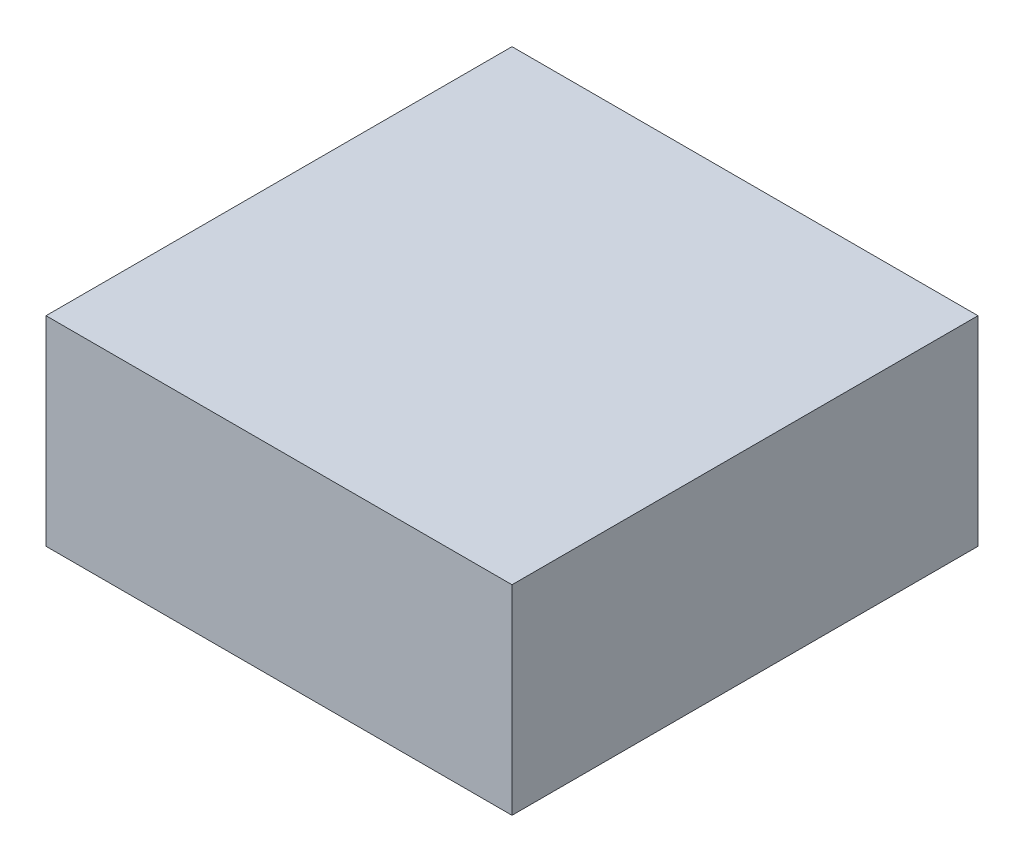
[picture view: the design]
ISO-10303-21;
HEADER;
FILE_DESCRIPTION(('STEP AP214'),'2;1');
FILE_NAME('part.step','',(''),(''),'','','');
FILE_SCHEMA(('AUTOMOTIVE_DESIGN { 1 0 10303 214 1 1 1 1 }'));
ENDSEC;
DATA;
#1=APPLICATION_CONTEXT('core data for automotive mechanical design processes');
#2=APPLICATION_PROTOCOL_DEFINITION('international standard','automotive_design',2000,#1);
#3=PRODUCT_CONTEXT('',#1,'mechanical');
#4=PRODUCT('Part','Part','',(#3));
#5=PRODUCT_RELATED_PRODUCT_CATEGORY('part','',(#4));
#6=PRODUCT_DEFINITION_FORMATION('','',#4);
#7=PRODUCT_DEFINITION_CONTEXT('part definition',#1,'design');
#8=PRODUCT_DEFINITION('design','',#6,#7);
#9=PRODUCT_DEFINITION_SHAPE('','',#8);
#10=(LENGTH_UNIT() NAMED_UNIT(*) SI_UNIT(.MILLI.,.METRE.));
#11=(NAMED_UNIT(*) PLANE_ANGLE_UNIT() SI_UNIT($,.RADIAN.));
#12=(NAMED_UNIT(*) SI_UNIT($,.STERADIAN.) SOLID_ANGLE_UNIT());
#13=UNCERTAINTY_MEASURE_WITH_UNIT(LENGTH_MEASURE(1.E-05),#10,'distance_accuracy_value','');
#14=(GEOMETRIC_REPRESENTATION_CONTEXT(3) GLOBAL_UNCERTAINTY_ASSIGNED_CONTEXT((#13)) GLOBAL_UNIT_ASSIGNED_CONTEXT((#10,
#11,#12)) REPRESENTATION_CONTEXT('',''));
#15=CARTESIAN_POINT('',(0.,0.,0.));
#16=DIRECTION('',(0.,0.,1.));
#17=DIRECTION('',(1.,0.,0.));
#18=AXIS2_PLACEMENT_3D('',#15,#16,#17);
#19=CARTESIAN_POINT('',(17.5,15.,17.5));
#20=DIRECTION('',(-1.,0.,0.));
#21=DIRECTION('',(0.,0.,1.));
#22=AXIS2_PLACEMENT_3D('',#19,#20,#21);
#23=PLANE('',#22);
#24=DIRECTION('',(0.,0.,-1.));
#25=VECTOR('',#24,1.);
#26=CARTESIAN_POINT('',(17.5,0.,17.5));
#27=LINE('',#26,#25);
#28=CARTESIAN_POINT('',(17.5,0.,17.5));
#29=VERTEX_POINT('',#28);
#30=CARTESIAN_POINT('',(17.5,0.,-17.5));
#31=VERTEX_POINT('',#30);
#32=EDGE_CURVE('E110',#29,#31,#27,.T.);
#33=ORIENTED_EDGE('',*,*,#32,.T.);
#34=DIRECTION('',(0.,-1.,0.));
#35=VECTOR('',#34,1.);
#36=CARTESIAN_POINT('',(17.5,15.,-17.5));
#37=LINE('',#36,#35);
#38=CARTESIAN_POINT('',(17.5,15.,-17.5));
#39=VERTEX_POINT('',#38);
#40=EDGE_CURVE('E12',#39,#31,#37,.T.);
#41=ORIENTED_EDGE('',*,*,#40,.F.);
#42=DIRECTION('',(0.,0.,-1.));
#43=VECTOR('',#42,1.);
#44=CARTESIAN_POINT('',(17.5,15.,17.5));
#45=LINE('',#44,#43);
#46=CARTESIAN_POINT('',(17.5,15.,17.5));
#47=VERTEX_POINT('',#46);
#48=EDGE_CURVE('E98',#47,#39,#45,.T.);
#49=ORIENTED_EDGE('',*,*,#48,.F.);
#50=DIRECTION('',(0.,-1.,0.));
#51=VECTOR('',#50,1.);
#52=CARTESIAN_POINT('',(17.5,15.,17.5));
#53=LINE('',#52,#51);
#54=EDGE_CURVE('E106',#47,#29,#53,.T.);
#55=ORIENTED_EDGE('',*,*,#54,.T.);
#56=EDGE_LOOP('',(#33,#41,#49,#55));
#57=FACE_BOUND('',#56,.T.);
#58=ADVANCED_FACE('F47',(#57),#23,.F.);
#59=CARTESIAN_POINT('',(-17.5,15.,-17.5));
#60=DIRECTION('',(0.,0.,1.));
#61=DIRECTION('',(1.,0.,0.));
#62=AXIS2_PLACEMENT_3D('',#59,#60,#61);
#63=PLANE('',#62);
#64=DIRECTION('',(-1.,0.,0.));
#65=VECTOR('',#64,1.);
#66=CARTESIAN_POINT('',(-17.5,0.,-17.5));
#67=LINE('',#66,#65);
#68=CARTESIAN_POINT('',(-17.5,0.,-17.5));
#69=VERTEX_POINT('',#68);
#70=EDGE_CURVE('E102',#31,#69,#67,.T.);
#71=ORIENTED_EDGE('',*,*,#70,.T.);
#72=DIRECTION('',(0.,-1.,0.));
#73=VECTOR('',#72,1.);
#74=CARTESIAN_POINT('',(-17.5,15.,-17.5));
#75=LINE('',#74,#73);
#76=CARTESIAN_POINT('',(-17.5,15.,-17.5));
#77=VERTEX_POINT('',#76);
#78=EDGE_CURVE('E55',#77,#69,#75,.T.);
#79=ORIENTED_EDGE('',*,*,#78,.F.);
#80=DIRECTION('',(-1.,0.,0.));
#81=VECTOR('',#80,1.);
#82=CARTESIAN_POINT('',(-17.5,15.,-17.5));
#83=LINE('',#82,#81);
#84=EDGE_CURVE('E93',#39,#77,#83,.T.);
#85=ORIENTED_EDGE('',*,*,#84,.F.);
#86=ORIENTED_EDGE('',*,*,#40,.T.);
#87=EDGE_LOOP('',(#71,#79,#85,#86));
#88=FACE_BOUND('',#87,.T.);
#89=ADVANCED_FACE('F101',(#88),#63,.F.);
#90=CARTESIAN_POINT('',(-17.5,15.,17.5));
#91=DIRECTION('',(1.,0.,0.));
#92=DIRECTION('',(0.,0.,-1.));
#93=AXIS2_PLACEMENT_3D('',#90,#91,#92);
#94=PLANE('',#93);
#95=DIRECTION('',(0.,0.,1.));
#96=VECTOR('',#95,1.);
#97=CARTESIAN_POINT('',(-17.5,0.,17.5));
#98=LINE('',#97,#96);
#99=CARTESIAN_POINT('',(-17.5,0.,17.5));
#100=VERTEX_POINT('',#99);
#101=EDGE_CURVE('E80',#69,#100,#98,.T.);
#102=ORIENTED_EDGE('',*,*,#101,.T.);
#103=DIRECTION('',(0.,-1.,0.));
#104=VECTOR('',#103,1.);
#105=CARTESIAN_POINT('',(-17.5,15.,17.5));
#106=LINE('',#105,#104);
#107=CARTESIAN_POINT('',(-17.5,15.,17.5));
#108=VERTEX_POINT('',#107);
#109=EDGE_CURVE('E103',#108,#100,#106,.T.);
#110=ORIENTED_EDGE('',*,*,#109,.F.);
#111=DIRECTION('',(0.,0.,1.));
#112=VECTOR('',#111,1.);
#113=CARTESIAN_POINT('',(-17.5,15.,17.5));
#114=LINE('',#113,#112);
#115=EDGE_CURVE('E96',#77,#108,#114,.T.);
#116=ORIENTED_EDGE('',*,*,#115,.F.);
#117=ORIENTED_EDGE('',*,*,#78,.T.);
#118=EDGE_LOOP('',(#102,#110,#116,#117));
#119=FACE_BOUND('',#118,.T.);
#120=ADVANCED_FACE('F104',(#119),#94,.F.);
#121=CARTESIAN_POINT('',(-17.5,15.,17.5));
#122=DIRECTION('',(0.,0.,-1.));
#123=DIRECTION('',(-1.,0.,0.));
#124=AXIS2_PLACEMENT_3D('',#121,#122,#123);
#125=PLANE('',#124);
#126=DIRECTION('',(1.,0.,0.));
#127=VECTOR('',#126,1.);
#128=CARTESIAN_POINT('',(-17.5,0.,17.5));
#129=LINE('',#128,#127);
#130=EDGE_CURVE('E86',#100,#29,#129,.T.);
#131=ORIENTED_EDGE('',*,*,#130,.T.);
#132=ORIENTED_EDGE('',*,*,#54,.F.);
#133=DIRECTION('',(1.,0.,0.));
#134=VECTOR('',#133,1.);
#135=CARTESIAN_POINT('',(-17.5,15.,17.5));
#136=LINE('',#135,#134);
#137=EDGE_CURVE('E63',#108,#47,#136,.T.);
#138=ORIENTED_EDGE('',*,*,#137,.F.);
#139=ORIENTED_EDGE('',*,*,#109,.T.);
#140=EDGE_LOOP('',(#131,#132,#138,#139));
#141=FACE_BOUND('',#140,.T.);
#142=ADVANCED_FACE('F117',(#141),#125,.F.);
#143=CARTESIAN_POINT('',(0.,15.,0.));
#144=DIRECTION('',(0.,-1.,0.));
#145=DIRECTION('',(0.,0.,-1.));
#146=AXIS2_PLACEMENT_3D('',#143,#144,#145);
#147=PLANE('',#146);
#148=ORIENTED_EDGE('',*,*,#48,.T.);
#149=ORIENTED_EDGE('',*,*,#84,.T.);
#150=ORIENTED_EDGE('',*,*,#115,.T.);
#151=ORIENTED_EDGE('',*,*,#137,.T.);
#152=EDGE_LOOP('',(#148,#149,#150,#151));
#153=FACE_BOUND('',#152,.T.);
#154=ADVANCED_FACE('F94',(#153),#147,.F.);
#155=CARTESIAN_POINT('',(0.,0.,0.));
#156=DIRECTION('',(0.,-1.,0.));
#157=DIRECTION('',(0.,0.,-1.));
#158=AXIS2_PLACEMENT_3D('',#155,#156,#157);
#159=PLANE('',#158);
#160=ORIENTED_EDGE('',*,*,#32,.F.);
#161=ORIENTED_EDGE('',*,*,#130,.F.);
#162=ORIENTED_EDGE('',*,*,#101,.F.);
#163=ORIENTED_EDGE('',*,*,#70,.F.);
#164=EDGE_LOOP('',(#160,#161,#162,#163));
#165=FACE_BOUND('',#164,.T.);
#166=ADVANCED_FACE('F120',(#165),#159,.T.);
#167=CLOSED_SHELL('',(#58,#89,#120,#142,#154,#166));
#168=MANIFOLD_SOLID_BREP('B2',#167);
#169=CARTESIAN_POINT('',(0.,4.,0.));
#170=DIRECTION('',(0.,-1.,0.));
#171=DIRECTION('',(0.,0.,-1.));
#172=AXIS2_PLACEMENT_3D('',#169,#170,#171);
#173=PLANE('',#172);
#174=CARTESIAN_POINT('',(0.,4.,0.));
#175=DIRECTION('',(0.,-1.,0.));
#176=DIRECTION('',(0.,0.,-1.));
#177=AXIS2_PLACEMENT_3D('',#174,#175,#176);
#178=CIRCLE('',#177,7.5);
#179=CARTESIAN_POINT('',(0.,4.,-7.5));
#180=VERTEX_POINT('',#179);
#181=EDGE_CURVE('E456',#180,#180,#178,.T.);
#182=ORIENTED_EDGE('',*,*,#181,.T.);
#183=EDGE_LOOP('',(#182));
#184=FACE_BOUND('',#183,.T.);
#185=ADVANCED_FACE('F170',(#184),#173,.T.);
#186=CARTESIAN_POINT('',(0.,4.,0.));
#187=DIRECTION('',(0.,-1.,0.));
#188=DIRECTION('',(0.,0.,-1.));
#189=AXIS2_PLACEMENT_3D('',#186,#187,#188);
#190=CONICAL_SURFACE('',#189,7.5,0.643501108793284);
#191=CARTESIAN_POINT('',(0.,0.,0.));
#192=DIRECTION('',(0.,-1.,0.));
#193=DIRECTION('',(0.,0.,-1.));
#194=AXIS2_PLACEMENT_3D('',#191,#192,#193);
#195=CIRCLE('',#194,10.5);
#196=CARTESIAN_POINT('',(0.,0.,-10.5));
#197=VERTEX_POINT('',#196);
#198=EDGE_CURVE('E453',#197,#197,#195,.T.);
#199=ORIENTED_EDGE('',*,*,#198,.T.);
#200=EDGE_LOOP('',(#199));
#201=FACE_BOUND('',#200,.T.);
#202=ORIENTED_EDGE('',*,*,#181,.F.);
#203=EDGE_LOOP('',(#202));
#204=FACE_BOUND('',#203,.T.);
#205=ADVANCED_FACE('F563',(#201,#204),#190,.F.);
#206=CARTESIAN_POINT('',(0.,0.,-10.5));
#207=DIRECTION('',(0.,-1.,0.));
#208=DIRECTION('',(0.,0.,-1.));
#209=AXIS2_PLACEMENT_3D('',#206,#207,#208);
#210=PLANE('',#209);
#211=ORIENTED_EDGE('',*,*,#198,.F.);
#212=EDGE_LOOP('',(#211));
#213=FACE_BOUND('',#212,.T.);
#214=CARTESIAN_POINT('',(0.,0.,0.));
#215=DIRECTION('',(0.,-1.,0.));
#216=DIRECTION('',(0.,0.,-1.));
#217=AXIS2_PLACEMENT_3D('',#214,#215,#216);
#218=CIRCLE('',#217,14.875);
#219=CARTESIAN_POINT('',(0.,0.,-14.875));
#220=VERTEX_POINT('',#219);
#221=EDGE_CURVE('E363',#220,#220,#218,.T.);
#222=ORIENTED_EDGE('',*,*,#221,.T.);
#223=EDGE_LOOP('',(#222));
#224=FACE_BOUND('',#223,.T.);
#225=ADVANCED_FACE('F571',(#213,#224),#210,.T.);
#226=CARTESIAN_POINT('',(0.,0.,0.));
#227=DIRECTION('',(0.,-1.,0.));
#228=DIRECTION('',(0.,0.,-1.));
#229=AXIS2_PLACEMENT_3D('',#226,#227,#228);
#230=CONICAL_SURFACE('',#229,14.875,0.643501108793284);
#231=CARTESIAN_POINT('',(0.,5.9,0.));
#232=DIRECTION('',(0.,-1.,0.));
#233=DIRECTION('',(0.,0.,-1.));
#234=AXIS2_PLACEMENT_3D('',#231,#232,#233);
#235=CIRCLE('',#234,10.45);
#236=CARTESIAN_POINT('',(0.,5.9,-10.45));
#237=VERTEX_POINT('',#236);
#238=EDGE_CURVE('E366',#237,#237,#235,.T.);
#239=ORIENTED_EDGE('',*,*,#238,.T.);
#240=EDGE_LOOP('',(#239));
#241=FACE_BOUND('',#240,.T.);
#242=ORIENTED_EDGE('',*,*,#221,.F.);
#243=EDGE_LOOP('',(#242));
#244=FACE_BOUND('',#243,.T.);
#245=ADVANCED_FACE('F641',(#241,#244),#230,.T.);
#246=CARTESIAN_POINT('',(0.,4.7,0.));
#247=DIRECTION('',(0.,-1.,0.));
#248=DIRECTION('',(0.,0.,-1.));
#249=AXIS2_PLACEMENT_3D('',#246,#247,#248);
#250=TOROIDAL_SURFACE('',#249,8.85,2.);
#251=CARTESIAN_POINT('',(0.,6.7,0.));
#252=DIRECTION('',(0.,-1.,0.));
#253=DIRECTION('',(0.,0.,-1.));
#254=AXIS2_PLACEMENT_3D('',#251,#252,#253);
#255=CIRCLE('',#254,8.85);
#256=CARTESIAN_POINT('',(0.,6.7,-8.85));
#257=VERTEX_POINT('',#256);
#258=EDGE_CURVE('E935',#257,#257,#255,.T.);
#259=ORIENTED_EDGE('',*,*,#258,.T.);
#260=EDGE_LOOP('',(#259));
#261=FACE_BOUND('',#260,.T.);
#262=ORIENTED_EDGE('',*,*,#238,.F.);
#263=EDGE_LOOP('',(#262));
#264=FACE_BOUND('',#263,.T.);
#265=ADVANCED_FACE('F627',(#261,#264),#250,.T.);
#266=CARTESIAN_POINT('',(0.,6.7,-8.85));
#267=DIRECTION('',(0.,1.,0.));
#268=DIRECTION('',(0.,0.,1.));
#269=AXIS2_PLACEMENT_3D('',#266,#267,#268);
#270=PLANE('',#269);
#271=DIRECTION('',(0.390432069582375,0.,-0.92063173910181));
#272=VECTOR('',#271,1.);
#273=CARTESIAN_POINT('',(-4.19533930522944,6.7,0.0590000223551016));
#274=LINE('',#273,#272);
#275=CARTESIAN_POINT('',(-4.44324414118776,6.7,0.643555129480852));
#276=VERTEX_POINT('',#275);
#277=CARTESIAN_POINT('',(-5.27922504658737,6.7,2.61478294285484));
#278=VERTEX_POINT('',#277);
#279=EDGE_CURVE('E415',#276,#278,#274,.F.);
#280=ORIENTED_EDGE('',*,*,#279,.F.);
#281=CARTESIAN_POINT('',(-3.97468030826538,6.7,0.901510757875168));
#282=DIRECTION('',(0.,1.,0.));
#283=DIRECTION('',(-0.435109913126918,0.,-0.900377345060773));
#284=AXIS2_PLACEMENT_3D('',#281,#282,#283);
#285=ELLIPSE('',#284,0.555470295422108,0.5);
#286=CARTESIAN_POINT('',(-3.88564907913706,6.7,0.374095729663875));
#287=VERTEX_POINT('',#286);
#288=EDGE_CURVE('E192',#276,#287,#285,.F.);
#289=ORIENTED_EDGE('',*,*,#288,.T.);
#290=DIRECTION('',(0.96393747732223,0.,0.266128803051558));
#291=VECTOR('',#290,1.);
#292=CARTESIAN_POINT('',(-1.45344472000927,6.7,1.04559118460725));
#293=LINE('',#292,#291);
#294=CARTESIAN_POINT('',(-2.14143502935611,6.7,0.85564729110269));
#295=VERTEX_POINT('',#294);
#296=EDGE_CURVE('E185',#295,#287,#293,.F.);
#297=ORIENTED_EDGE('',*,*,#296,.F.);
#298=CARTESIAN_POINT('',(-2.34213496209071,6.7,1.35223225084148));
#299=DIRECTION('',(0.,1.,0.));
#300=DIRECTION('',(0.866025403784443,0.,-0.499999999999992));
#301=AXIS2_PLACEMENT_3D('',#298,#299,#300);
#302=ELLIPSE('',#301,0.561470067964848,0.5);
#303=CARTESIAN_POINT('',(-1.81172980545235,6.7,1.42671349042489));
#304=VERTEX_POINT('',#303);
#305=EDGE_CURVE('E411',#295,#304,#302,.F.);
#306=ORIENTED_EDGE('',*,*,#305,.T.);
#307=DIRECTION('',(-0.251494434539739,0.,0.967858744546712));
#308=VECTOR('',#307,1.);
#309=CARTESIAN_POINT('',(-2.42648733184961,6.7,3.79256484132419));
#310=LINE('',#309,#308);
#311=CARTESIAN_POINT('',(-2.26680094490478,6.7,3.17802294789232));
#312=VERTEX_POINT('',#311);
#313=EDGE_CURVE('E403',#312,#304,#310,.F.);
#314=ORIENTED_EDGE('',*,*,#313,.F.);
#315=CARTESIAN_POINT('',(-2.7680713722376,6.7,2.99141873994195));
#316=DIRECTION('',(0.,1.,0.));
#317=DIRECTION('',(0.562194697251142,0.,0.827004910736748));
#318=AXIS2_PLACEMENT_3D('',#315,#316,#317);
#319=ELLIPSE('',#318,0.555470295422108,0.5);
#320=CARTESIAN_POINT('',(-2.77895716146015,6.7,3.52618473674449));
#321=VERTEX_POINT('',#320);
#322=EDGE_CURVE('E400',#312,#321,#319,.F.);
#323=ORIENTED_EDGE('',*,*,#322,.T.);
#324=DIRECTION('',(-0.9925065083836,0.,-0.122191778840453));
#325=VECTOR('',#324,1.);
#326=CARTESIAN_POINT('',(-5.85784082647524,6.7,3.14713002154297));
#327=LINE('',#326,#325);
#328=CARTESIAN_POINT('',(-4.90408097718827,6.7,3.26455153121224));
#329=VERTEX_POINT('',#328);
#330=EDGE_CURVE('E405',#329,#321,#327,.F.);
#331=ORIENTED_EDGE('',*,*,#330,.F.);
#332=CARTESIAN_POINT('',(-4.75713974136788,6.7,2.74653591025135));
#333=DIRECTION('',(0.,1.,0.));
#334=DIRECTION('',(-0.866025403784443,0.,0.499999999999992));
#335=AXIS2_PLACEMENT_3D('',#332,#333,#334);
#336=ELLIPSE('',#335,0.584262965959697,0.5);
#337=EDGE_CURVE('E408',#329,#278,#336,.F.);
#338=ORIENTED_EDGE('',*,*,#337,.T.);
#339=EDGE_LOOP('',(#280,#289,#297,#306,#314,#323,#331,#338));
#340=FACE_BOUND('',#339,.T.);
#341=DIRECTION('',(-0.992506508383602,0.,0.122191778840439));
#342=VECTOR('',#341,1.);
#343=CARTESIAN_POINT('',(2.14876517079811,6.7,3.60377040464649));
#344=LINE('',#343,#342);
#345=CARTESIAN_POINT('',(2.7789571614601,6.7,3.52618473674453));
#346=VERTEX_POINT('',#345);
#347=CARTESIAN_POINT('',(4.90408097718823,6.7,3.2645515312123));
#348=VERTEX_POINT('',#347);
#349=EDGE_CURVE('E395',#346,#348,#344,.F.);
#350=ORIENTED_EDGE('',*,*,#349,.F.);
#351=CARTESIAN_POINT('',(2.76807137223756,6.7,2.99141873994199));
#352=DIRECTION('',(0.,1.,0.));
#353=DIRECTION('',(-0.562194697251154,0.,0.827004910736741));
#354=AXIS2_PLACEMENT_3D('',#351,#352,#353);
#355=ELLIPSE('',#354,0.555470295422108,0.5);
#356=CARTESIAN_POINT('',(2.26680094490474,6.7,3.17802294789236));
#357=VERTEX_POINT('',#356);
#358=EDGE_CURVE('E397',#346,#357,#355,.F.);
#359=ORIENTED_EDGE('',*,*,#358,.T.);
#360=DIRECTION('',(-0.251494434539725,0.,-0.967858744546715));
#361=VECTOR('',#360,1.);
#362=CARTESIAN_POINT('',(1.63223088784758,6.7,0.735924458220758));
#363=LINE('',#362,#361);
#364=CARTESIAN_POINT('',(1.81172980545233,6.7,1.42671349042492));
#365=VERTEX_POINT('',#364);
#366=EDGE_CURVE('E393',#365,#357,#363,.F.);
#367=ORIENTED_EDGE('',*,*,#366,.F.);
#368=CARTESIAN_POINT('',(2.3421349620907,6.7,1.35223225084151));
#369=DIRECTION('',(0.,1.,0.));
#370=DIRECTION('',(-0.866025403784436,0.,-0.500000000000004));
#371=AXIS2_PLACEMENT_3D('',#368,#369,#370);
#372=ELLIPSE('',#371,0.561470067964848,0.5);
#373=CARTESIAN_POINT('',(2.1414350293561,6.7,0.855647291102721));
#374=VERTEX_POINT('',#373);
#375=EDGE_CURVE('E390',#365,#374,#372,.F.);
#376=ORIENTED_EDGE('',*,*,#375,.T.);
#377=DIRECTION('',(0.963937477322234,0.,-0.266128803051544));
#378=VECTOR('',#377,1.);
#379=CARTESIAN_POINT('',(4.49770116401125,6.7,0.205117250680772));
#380=LINE('',#379,#378);
#381=CARTESIAN_POINT('',(3.88564907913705,6.7,0.37409572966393));
#382=VERTEX_POINT('',#381);
#383=EDGE_CURVE('E382',#382,#374,#380,.F.);
#384=ORIENTED_EDGE('',*,*,#383,.F.);
#385=CARTESIAN_POINT('',(3.97468030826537,6.7,0.901510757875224));
#386=DIRECTION('',(0.,1.,0.));
#387=DIRECTION('',(0.435109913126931,0.,-0.900377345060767));
#388=AXIS2_PLACEMENT_3D('',#385,#386,#387);
#389=ELLIPSE('',#388,0.555470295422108,0.5);
#390=CARTESIAN_POINT('',(4.44324414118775,6.7,0.643555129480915));
#391=VERTEX_POINT('',#390);
#392=EDGE_CURVE('E379',#382,#391,#389,.F.);
#393=ORIENTED_EDGE('',*,*,#392,.T.);
#394=DIRECTION('',(0.390432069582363,0.,0.920631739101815));
#395=VECTOR('',#394,1.);
#396=CARTESIAN_POINT('',(5.65441496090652,6.7,3.49947395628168));
#397=LINE('',#396,#395);
#398=CARTESIAN_POINT('',(5.27922504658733,6.7,2.61478294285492));
#399=VERTEX_POINT('',#398);
#400=EDGE_CURVE('E384',#399,#391,#397,.F.);
#401=ORIENTED_EDGE('',*,*,#400,.F.);
#402=CARTESIAN_POINT('',(4.75713974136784,6.7,2.74653591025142));
#403=DIRECTION('',(0.,1.,0.));
#404=DIRECTION('',(0.866025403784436,0.,0.500000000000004));
#405=AXIS2_PLACEMENT_3D('',#402,#403,#404);
#406=ELLIPSE('',#405,0.584262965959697,0.5);
#407=EDGE_CURVE('E387',#399,#348,#406,.F.);
#408=ORIENTED_EDGE('',*,*,#407,.T.);
#409=EDGE_LOOP('',(#350,#359,#367,#376,#384,#393,#401,#408));
#410=FACE_BOUND('',#409,.T.);
#411=DIRECTION('',(0.602074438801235,0.,0.79843996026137));
#412=VECTOR('',#411,1.);
#413=CARTESIAN_POINT('',(2.04657413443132,6.7,-3.66277042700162));
#414=LINE('',#413,#412);
#415=CARTESIAN_POINT('',(1.66428697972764,6.7,-4.16973986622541));
#416=VERTEX_POINT('',#415);
#417=CARTESIAN_POINT('',(0.375144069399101,6.7,-5.87933447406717));
#418=VERTEX_POINT('',#417);
#419=EDGE_CURVE('E374',#416,#418,#414,.F.);
#420=ORIENTED_EDGE('',*,*,#419,.F.);
#421=CARTESIAN_POINT('',(1.2066089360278,6.7,-3.89292949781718));
#422=DIRECTION('',(0.,1.,0.));
#423=DIRECTION('',(0.997304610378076,0.,0.0733724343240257));
#424=AXIS2_PLACEMENT_3D('',#421,#422,#423);
#425=ELLIPSE('',#424,0.555470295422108,0.5);
#426=CARTESIAN_POINT('',(1.6188481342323,6.7,-3.55211867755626));
#427=VERTEX_POINT('',#426);
#428=EDGE_CURVE('E376',#416,#427,#425,.F.);
#429=ORIENTED_EDGE('',*,*,#428,.T.);
#430=DIRECTION('',(-0.712443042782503,0.,0.701729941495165));
#431=VECTOR('',#430,1.);
#432=CARTESIAN_POINT('',(-0.178786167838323,6.7,-1.78151564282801));
#433=LINE('',#432,#431);
#434=CARTESIAN_POINT('',(0.329705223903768,6.7,-2.28236078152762));
#435=VERTEX_POINT('',#434);
#436=EDGE_CURVE('E372',#435,#427,#433,.F.);
#437=ORIENTED_EDGE('',*,*,#436,.F.);
#438=CARTESIAN_POINT('',(0.,6.7,-2.704464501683));
#439=DIRECTION('',(0.,1.,0.));
#440=DIRECTION('',(0.,0.,1.));
#441=AXIS2_PLACEMENT_3D('',#438,#439,#440);
#442=ELLIPSE('',#441,0.561470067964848,0.5);
#443=CARTESIAN_POINT('',(-0.329705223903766,6.7,-2.28236078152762));
#444=VERTEX_POINT('',#443);
#445=EDGE_CURVE('E360',#435,#444,#442,.F.);
#446=ORIENTED_EDGE('',*,*,#445,.T.);
#447=DIRECTION('',(-0.712443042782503,0.,-0.701729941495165));
#448=VECTOR('',#447,1.);
#449=CARTESIAN_POINT('',(-2.07121383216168,6.7,-3.99768209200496));
#450=LINE('',#449,#448);
#451=CARTESIAN_POINT('',(-1.6188481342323,6.7,-3.55211867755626));
#452=VERTEX_POINT('',#451);
#453=EDGE_CURVE('E352',#452,#444,#450,.F.);
#454=ORIENTED_EDGE('',*,*,#453,.F.);
#455=CARTESIAN_POINT('',(-1.20660893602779,6.7,-3.89292949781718));
#456=DIRECTION('',(0.,1.,0.));
#457=DIRECTION('',(-0.997304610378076,0.,0.0733724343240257));
#458=AXIS2_PLACEMENT_3D('',#455,#456,#457);
#459=ELLIPSE('',#458,0.555470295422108,0.5);
#460=CARTESIAN_POINT('',(-1.66428697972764,6.7,-4.16973986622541));
#461=VERTEX_POINT('',#460);
#462=EDGE_CURVE('E45',#452,#461,#459,.F.);
#463=ORIENTED_EDGE('',*,*,#462,.T.);
#464=DIRECTION('',(0.602074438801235,0.,-0.79843996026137));
#465=VECTOR('',#464,1.);
#466=CARTESIAN_POINT('',(0.20342586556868,6.7,-6.64660397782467));
#467=LINE('',#466,#465);
#468=CARTESIAN_POINT('',(-0.375144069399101,6.7,-5.87933447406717));
#469=VERTEX_POINT('',#468);
#470=EDGE_CURVE('E346',#469,#461,#467,.F.);
#471=ORIENTED_EDGE('',*,*,#470,.F.);
#472=CARTESIAN_POINT('',(0.,6.7,-5.49307182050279));
#473=DIRECTION('',(0.,1.,0.));
#474=DIRECTION('',(0.,0.,-1.));
#475=AXIS2_PLACEMENT_3D('',#472,#473,#474);
#476=ELLIPSE('',#475,0.584262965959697,0.5);
#477=EDGE_CURVE('E351',#469,#418,#476,.F.);
#478=ORIENTED_EDGE('',*,*,#477,.T.);
#479=EDGE_LOOP('',(#420,#429,#437,#446,#454,#463,#471,#478));
#480=FACE_BOUND('',#479,.T.);
#481=ORIENTED_EDGE('',*,*,#258,.F.);
#482=EDGE_LOOP('',(#481));
#483=FACE_BOUND('',#482,.T.);
#484=ADVANCED_FACE('F356',(#340,#410,#480,#483),#270,.T.);
#485=CARTESIAN_POINT('',(0.,7.,0.));
#486=DIRECTION('',(0.,-1.,0.));
#487=DIRECTION('',(0.,0.,-1.));
#488=AXIS2_PLACEMENT_3D('',#485,#486,#487);
#489=PLANE('',#488);
#490=DIRECTION('',(0.602074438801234,0.,-0.79843996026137));
#491=VECTOR('',#490,1.);
#492=CARTESIAN_POINT('',(-2.97828959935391,7.,-2.24581950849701));
#493=LINE('',#492,#491);
#494=CARTESIAN_POINT('',(-0.375144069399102,7.,-5.69797638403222));
#495=VERTEX_POINT('',#494);
#496=CARTESIAN_POINT('',(-1.51949906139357,7.,-4.18039201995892));
#497=VERTEX_POINT('',#496);
#498=EDGE_CURVE('E445',#495,#497,#493,.F.);
#499=ORIENTED_EDGE('',*,*,#498,.T.);
#500=CARTESIAN_POINT('',(-1.06182101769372,7.,-3.90358165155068));
#501=DIRECTION('',(0.,-1.,0.));
#502=DIRECTION('',(-0.997304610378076,0.,0.0733724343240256));
#503=AXIS2_PLACEMENT_3D('',#500,#501,#502);
#504=ELLIPSE('',#503,0.555470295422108,0.5);
#505=CARTESIAN_POINT('',(-1.47406021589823,7.,-3.56277083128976));
#506=VERTEX_POINT('',#505);
#507=EDGE_CURVE('E337',#497,#506,#504,.F.);
#508=ORIENTED_EDGE('',*,*,#507,.T.);
#509=DIRECTION('',(-0.712443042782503,0.,-0.701729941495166));
#510=VECTOR('',#509,1.);
#511=CARTESIAN_POINT('',(1.05531699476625,7.,-1.07142820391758));
#512=LINE('',#511,#510);
#513=CARTESIAN_POINT('',(-0.329705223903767,7.,-2.43562365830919));
#514=VERTEX_POINT('',#513);
#515=EDGE_CURVE('E447',#506,#514,#512,.F.);
#516=ORIENTED_EDGE('',*,*,#515,.T.);
#517=CARTESIAN_POINT('',(0.,7.,-2.85772737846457));
#518=DIRECTION('',(0.,-1.,0.));
#519=DIRECTION('',(0.,0.,1.));
#520=AXIS2_PLACEMENT_3D('',#517,#518,#519);
#521=ELLIPSE('',#520,0.561470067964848,0.5);
#522=CARTESIAN_POINT('',(0.329705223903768,7.,-2.43562365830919));
#523=VERTEX_POINT('',#522);
#524=EDGE_CURVE('E521',#514,#523,#521,.F.);
#525=ORIENTED_EDGE('',*,*,#524,.T.);
#526=DIRECTION('',(-0.712443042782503,0.,0.701729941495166));
#527=VECTOR('',#526,1.);
#528=CARTESIAN_POINT('',(-1.05531699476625,7.,-1.07142820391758));
#529=LINE('',#528,#527);
#530=CARTESIAN_POINT('',(1.47406021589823,7.,-3.56277083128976));
#531=VERTEX_POINT('',#530);
#532=EDGE_CURVE('E450',#523,#531,#529,.F.);
#533=ORIENTED_EDGE('',*,*,#532,.T.);
#534=CARTESIAN_POINT('',(1.06182101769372,7.,-3.90358165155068));
#535=DIRECTION('',(0.,-1.,0.));
#536=DIRECTION('',(0.997304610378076,0.,0.0733724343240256));
#537=AXIS2_PLACEMENT_3D('',#534,#535,#536);
#538=ELLIPSE('',#537,0.555470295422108,0.5);
#539=CARTESIAN_POINT('',(1.51949906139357,7.,-4.18039201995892));
#540=VERTEX_POINT('',#539);
#541=EDGE_CURVE('E341',#531,#540,#538,.F.);
#542=ORIENTED_EDGE('',*,*,#541,.T.);
#543=DIRECTION('',(0.602074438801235,0.,0.79843996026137));
#544=VECTOR('',#543,1.);
#545=CARTESIAN_POINT('',(2.97828959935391,7.,-2.24581950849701));
#546=LINE('',#545,#544);
#547=CARTESIAN_POINT('',(0.375144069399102,7.,-5.69797638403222));
#548=VERTEX_POINT('',#547);
#549=EDGE_CURVE('E442',#540,#548,#546,.F.);
#550=ORIENTED_EDGE('',*,*,#549,.T.);
#551=CARTESIAN_POINT('',(0.,7.,-5.31171373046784));
#552=DIRECTION('',(0.,-1.,0.));
#553=DIRECTION('',(0.,0.,-1.));
#554=AXIS2_PLACEMENT_3D('',#551,#552,#553);
#555=ELLIPSE('',#554,0.584262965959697,0.5);
#556=EDGE_CURVE('E519',#548,#495,#555,.F.);
#557=ORIENTED_EDGE('',*,*,#556,.T.);
#558=EDGE_LOOP('',(#499,#508,#516,#525,#533,#542,#550,#557));
#559=FACE_BOUND('',#558,.T.);
#560=ADVANCED_FACE('F539',(#559),#489,.F.);
#561=CARTESIAN_POINT('',(1.67832694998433,5.72260212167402,-3.85822485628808));
#562=DIRECTION('',(0.434430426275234,-0.900138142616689,0.0319613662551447));
#563=DIRECTION('',(0.900598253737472,0.434652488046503,0.));
#564=AXIS2_PLACEMENT_3D('',#561,#562,#563);
#565=CYLINDRICAL_SURFACE('',#564,0.5);
#566=ORIENTED_EDGE('',*,*,#428,.F.);
#567=DIRECTION('',(-0.434430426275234,0.900138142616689,-0.0319613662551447));
#568=VECTOR('',#567,1.);
#569=CARTESIAN_POINT('',(2.05347101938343,5.89361219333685,-4.14110730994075));
#570=LINE('',#569,#568);
#571=EDGE_CURVE('E529',#540,#416,#570,.F.);
#572=ORIENTED_EDGE('',*,*,#571,.F.);
#573=ORIENTED_EDGE('',*,*,#541,.F.);
#574=DIRECTION('',(-0.434430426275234,0.900138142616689,-0.0319613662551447));
#575=VECTOR('',#574,1.);
#576=CARTESIAN_POINT('',(1.61416158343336,6.70971051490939,-3.55246347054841));
#577=LINE('',#576,#575);
#578=EDGE_CURVE('E524',#427,#531,#577,.T.);
#579=ORIENTED_EDGE('',*,*,#578,.F.);
#580=EDGE_LOOP('',(#566,#572,#573,#579));
#581=FACE_BOUND('',#580,.T.);
#582=ADVANCED_FACE('F172',(#581),#565,.T.);
#583=CARTESIAN_POINT('',(0.,5.6974225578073,-2.19227149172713));
#584=DIRECTION('',(0.,-0.890519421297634,0.454945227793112));
#585=DIRECTION('',(0.,-0.454945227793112,-0.890519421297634));
#586=AXIS2_PLACEMENT_3D('',#583,#584,#585);
#587=CYLINDRICAL_SURFACE('',#586,0.5);
#588=ORIENTED_EDGE('',*,*,#445,.F.);
#589=DIRECTION('',(0.,0.890519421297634,-0.454945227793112));
#590=VECTOR('',#589,1.);
#591=CARTESIAN_POINT('',(0.329705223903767,5.86843262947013,-1.85753275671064));
#592=LINE('',#591,#590);
#593=EDGE_CURVE('E526',#523,#435,#592,.F.);
#594=ORIENTED_EDGE('',*,*,#593,.F.);
#595=ORIENTED_EDGE('',*,*,#524,.F.);
#596=DIRECTION('',(0.,0.890519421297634,-0.454945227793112));
#597=VECTOR('',#596,1.);
#598=CARTESIAN_POINT('',(-0.329705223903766,6.7662848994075,-2.31622416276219));
#599=LINE('',#598,#597);
#600=EDGE_CURVE('E513',#444,#514,#599,.T.);
#601=ORIENTED_EDGE('',*,*,#600,.F.);
#602=EDGE_LOOP('',(#588,#594,#595,#601));
#603=FACE_BOUND('',#602,.T.);
#604=ADVANCED_FACE('F551',(#603),#587,.T.);
#605=CARTESIAN_POINT('',(0.,6.,-1.6));
#606=DIRECTION('',(0.659410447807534,0.342020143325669,0.669477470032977));
#607=DIRECTION('',(0.712443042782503,0.,-0.701729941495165));
#608=AXIS2_PLACEMENT_3D('',#605,#606,#607);
#609=PLANE('',#608);
#610=ORIENTED_EDGE('',*,*,#593,.T.);
#611=ORIENTED_EDGE('',*,*,#436,.T.);
#612=ORIENTED_EDGE('',*,*,#578,.T.);
#613=ORIENTED_EDGE('',*,*,#532,.F.);
#614=EDGE_LOOP('',(#610,#611,#612,#613));
#615=FACE_BOUND('',#614,.T.);
#616=ADVANCED_FACE('F546',(#615),#609,.T.);
#617=CARTESIAN_POINT('',(-1.67832694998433,5.72260212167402,-3.85822485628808));
#618=DIRECTION('',(-0.434430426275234,-0.900138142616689,0.0319613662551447));
#619=DIRECTION('',(0.900598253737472,-0.434652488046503,0.));
#620=AXIS2_PLACEMENT_3D('',#617,#618,#619);
#621=CYLINDRICAL_SURFACE('',#620,0.5);
#622=ORIENTED_EDGE('',*,*,#462,.F.);
#623=DIRECTION('',(0.434430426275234,0.900138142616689,-0.0319613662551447));
#624=VECTOR('',#623,1.);
#625=CARTESIAN_POINT('',(-2.00803217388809,5.89361219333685,-3.52348612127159));
#626=LINE('',#625,#624);
#627=EDGE_CURVE('E515',#506,#452,#626,.F.);
#628=ORIENTED_EDGE('',*,*,#627,.F.);
#629=ORIENTED_EDGE('',*,*,#507,.F.);
#630=DIRECTION('',(0.434430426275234,0.900138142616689,-0.0319613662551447));
#631=VECTOR('',#630,1.);
#632=CARTESIAN_POINT('',(-1.58739848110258,6.85931266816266,-4.17539660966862));
#633=LINE('',#632,#631);
#634=EDGE_CURVE('E332',#461,#497,#633,.T.);
#635=ORIENTED_EDGE('',*,*,#634,.F.);
#636=EDGE_LOOP('',(#622,#628,#629,#635));
#637=FACE_BOUND('',#636,.T.);
#638=ADVANCED_FACE('F334',(#637),#621,.T.);
#639=CARTESIAN_POINT('',(-2.25,6.,-3.81616644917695));
#640=DIRECTION('',(-0.659410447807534,0.342020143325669,0.669477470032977));
#641=DIRECTION('',(0.712443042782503,0.,0.701729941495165));
#642=AXIS2_PLACEMENT_3D('',#639,#640,#641);
#643=PLANE('',#642);
#644=ORIENTED_EDGE('',*,*,#627,.T.);
#645=ORIENTED_EDGE('',*,*,#453,.T.);
#646=ORIENTED_EDGE('',*,*,#600,.T.);
#647=ORIENTED_EDGE('',*,*,#515,.F.);
#648=EDGE_LOOP('',(#644,#645,#646,#647));
#649=FACE_BOUND('',#648,.T.);
#650=ADVANCED_FACE('F552',(#649),#643,.T.);
#651=CARTESIAN_POINT('',(0.,5.60873322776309,-6.15277201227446));
#652=DIRECTION('',(0.,-0.855779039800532,-0.517341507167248));
#653=DIRECTION('',(0.,0.517341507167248,-0.855779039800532));
#654=AXIS2_PLACEMENT_3D('',#651,#652,#653);
#655=CYLINDRICAL_SURFACE('',#654,0.5);
#656=ORIENTED_EDGE('',*,*,#477,.F.);
#657=DIRECTION('',(0.,0.855779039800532,0.517341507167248));
#658=VECTOR('',#657,1.);
#659=CARTESIAN_POINT('',(-0.375144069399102,5.77974329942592,-6.43565446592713));
#660=LINE('',#659,#658);
#661=EDGE_CURVE('E342',#495,#469,#660,.F.);
#662=ORIENTED_EDGE('',*,*,#661,.F.);
#663=ORIENTED_EDGE('',*,*,#556,.F.);
#664=DIRECTION('',(0.,0.855779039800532,0.517341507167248));
#665=VECTOR('',#664,1.);
#666=CARTESIAN_POINT('',(0.375144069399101,7.10077598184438,-5.63705458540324));
#667=LINE('',#666,#665);
#668=EDGE_CURVE('E178',#418,#548,#667,.T.);
#669=ORIENTED_EDGE('',*,*,#668,.F.);
#670=EDGE_LOOP('',(#656,#662,#663,#669));
#671=FACE_BOUND('',#670,.T.);
#672=ADVANCED_FACE('F541',(#671),#655,.T.);
#673=CARTESIAN_POINT('',(0.,6.,-6.8));
#674=DIRECTION('',(-0.750288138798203,0.342020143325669,-0.565764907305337));
#675=DIRECTION('',(-0.602074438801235,0.,0.79843996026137));
#676=AXIS2_PLACEMENT_3D('',#673,#674,#675);
#677=PLANE('',#676);
#678=ORIENTED_EDGE('',*,*,#661,.T.);
#679=ORIENTED_EDGE('',*,*,#470,.T.);
#680=ORIENTED_EDGE('',*,*,#634,.T.);
#681=ORIENTED_EDGE('',*,*,#498,.F.);
#682=EDGE_LOOP('',(#678,#679,#680,#681));
#683=FACE_BOUND('',#682,.T.);
#684=ADVANCED_FACE('F347',(#683),#677,.T.);
#685=CARTESIAN_POINT('',(2.25,6.,-3.81616644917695));
#686=DIRECTION('',(0.750288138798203,0.342020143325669,-0.565764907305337));
#687=DIRECTION('',(-0.602074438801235,0.,-0.79843996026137));
#688=AXIS2_PLACEMENT_3D('',#685,#686,#687);
#689=PLANE('',#688);
#690=ORIENTED_EDGE('',*,*,#571,.T.);
#691=ORIENTED_EDGE('',*,*,#419,.T.);
#692=ORIENTED_EDGE('',*,*,#668,.T.);
#693=ORIENTED_EDGE('',*,*,#549,.F.);
#694=EDGE_LOOP('',(#690,#691,#692,#693));
#695=FACE_BOUND('',#694,.T.);
#696=ADVANCED_FACE('F534',(#695),#689,.T.);
#697=CARTESIAN_POINT('',(0.,7.,0.));
#698=DIRECTION('',(0.,-1.,0.));
#699=DIRECTION('',(0.866025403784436,0.,0.500000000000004));
#700=AXIS2_PLACEMENT_3D('',#697,#698,#699);
#701=PLANE('',#700);
#702=DIRECTION('',(0.390432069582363,0.,0.920631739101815));
#703=VECTOR('',#702,1.);
#704=CARTESIAN_POINT('',(3.43408154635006,7.,-1.45636469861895));
#705=LINE('',#704,#703);
#706=CARTESIAN_POINT('',(5.12216433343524,7.,2.52410389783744));
#707=VERTEX_POINT('',#706);
#708=CARTESIAN_POINT('',(4.38007521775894,7.,0.77427122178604));
#709=VERTEX_POINT('',#708);
#710=EDGE_CURVE('E433',#707,#709,#705,.F.);
#711=ORIENTED_EDGE('',*,*,#710,.T.);
#712=CARTESIAN_POINT('',(3.91151138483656,7.,1.03222685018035));
#713=DIRECTION('',(0.,-1.,0.));
#714=DIRECTION('',(0.435109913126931,0.,-0.900377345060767));
#715=AXIS2_PLACEMENT_3D('',#712,#713,#714);
#716=ELLIPSE('',#715,0.555470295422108,0.5);
#717=CARTESIAN_POINT('',(3.82248015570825,7.,0.504811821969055));
#718=VERTEX_POINT('',#717);
#719=EDGE_CURVE('E501',#709,#718,#716,.F.);
#720=ORIENTED_EDGE('',*,*,#719,.T.);
#721=DIRECTION('',(0.963937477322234,0.,-0.266128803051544));
#722=VECTOR('',#721,1.);
#723=CARTESIAN_POINT('',(0.400225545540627,7.,1.44964542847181));
#724=LINE('',#723,#722);
#725=CARTESIAN_POINT('',(2.27416457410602,7.,0.932278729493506));
#726=VERTEX_POINT('',#725);
#727=EDGE_CURVE('E436',#718,#726,#724,.F.);
#728=ORIENTED_EDGE('',*,*,#727,.T.);
#729=CARTESIAN_POINT('',(2.47486450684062,7.,1.4288636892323));
#730=DIRECTION('',(0.,-1.,0.));
#731=DIRECTION('',(-0.866025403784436,0.,-0.500000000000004));
#732=AXIS2_PLACEMENT_3D('',#729,#730,#731);
#733=ELLIPSE('',#732,0.561470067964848,0.5);
#734=CARTESIAN_POINT('',(1.94445935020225,7.,1.5033449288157));
#735=VERTEX_POINT('',#734);
#736=EDGE_CURVE('E499',#726,#735,#733,.F.);
#737=ORIENTED_EDGE('',*,*,#736,.T.);
#738=DIRECTION('',(-0.251494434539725,0.,-0.967858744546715));
#739=VECTOR('',#738,1.);
#740=CARTESIAN_POINT('',(1.45554254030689,7.,-0.378217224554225));
#741=LINE('',#740,#739);
#742=CARTESIAN_POINT('',(2.34841993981,7.,3.05795900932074));
#743=VERTEX_POINT('',#742);
#744=EDGE_CURVE('E439',#735,#743,#741,.F.);
#745=ORIENTED_EDGE('',*,*,#744,.T.);
#746=CARTESIAN_POINT('',(2.84969036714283,7.,2.87135480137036));
#747=DIRECTION('',(0.,-1.,0.));
#748=DIRECTION('',(-0.562194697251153,0.,0.82700491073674));
#749=AXIS2_PLACEMENT_3D('',#746,#747,#748);
#750=ELLIPSE('',#749,0.555470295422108,0.5);
#751=CARTESIAN_POINT('',(2.86057615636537,7.,3.40612079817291));
#752=VERTEX_POINT('',#751);
#753=EDGE_CURVE('E497',#743,#752,#750,.F.);
#754=ORIENTED_EDGE('',*,*,#753,.T.);
#755=DIRECTION('',(-0.992506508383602,0.,0.122191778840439));
#756=VECTOR('',#755,1.);
#757=CARTESIAN_POINT('',(0.455791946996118,7.,3.70218420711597));
#758=LINE('',#757,#756);
#759=CARTESIAN_POINT('',(4.74702026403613,7.,3.17387248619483));
#760=VERTEX_POINT('',#759);
#761=EDGE_CURVE('E430',#752,#760,#758,.F.);
#762=ORIENTED_EDGE('',*,*,#761,.T.);
#763=CARTESIAN_POINT('',(4.60007902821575,7.,2.65585686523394));
#764=DIRECTION('',(0.,-1.,0.));
#765=DIRECTION('',(0.866025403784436,0.,0.500000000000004));
#766=AXIS2_PLACEMENT_3D('',#763,#764,#765);
#767=ELLIPSE('',#766,0.584262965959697,0.5);
#768=EDGE_CURVE('E495',#760,#707,#767,.F.);
#769=ORIENTED_EDGE('',*,*,#768,.T.);
#770=EDGE_LOOP('',(#711,#720,#728,#737,#745,#754,#762,#769));
#771=FACE_BOUND('',#770,.T.);
#772=ADVANCED_FACE('F612',(#771),#701,.F.);
#773=CARTESIAN_POINT('',(2.50215726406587,5.72260212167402,3.38258620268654));
#774=DIRECTION('',(-0.244894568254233,-0.900138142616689,0.360247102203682));
#775=DIRECTION('',(0.,-0.371561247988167,-0.928408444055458));
#776=AXIS2_PLACEMENT_3D('',#773,#774,#775);
#777=CYLINDRICAL_SURFACE('',#776,0.5);
#778=ORIENTED_EDGE('',*,*,#358,.F.);
#779=DIRECTION('',(0.244894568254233,0.900138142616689,-0.360247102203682));
#780=VECTOR('',#779,1.);
#781=CARTESIAN_POINT('',(2.5595686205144,5.89361219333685,3.84891172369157));
#782=LINE('',#781,#780);
#783=EDGE_CURVE('E510',#752,#346,#782,.F.);
#784=ORIENTED_EDGE('',*,*,#783,.F.);
#785=ORIENTED_EDGE('',*,*,#753,.F.);
#786=DIRECTION('',(0.244894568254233,0.900138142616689,-0.360247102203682));
#787=VECTOR('',#786,1.);
#788=CARTESIAN_POINT('',(2.26944281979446,6.70971051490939,3.17413667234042));
#789=LINE('',#788,#787);
#790=EDGE_CURVE('E503',#357,#743,#789,.T.);
#791=ORIENTED_EDGE('',*,*,#790,.F.);
#792=EDGE_LOOP('',(#778,#784,#785,#791));
#793=FACE_BOUND('',#792,.T.);
#794=ADVANCED_FACE('F609',(#793),#777,.T.);
#795=CARTESIAN_POINT('',(1.8985628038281,5.6974225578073,1.09613574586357));
#796=DIRECTION('',(-0.393994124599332,-0.890519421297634,-0.227472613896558));
#797=DIRECTION('',(0.914493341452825,-0.40460094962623,0.));
#798=AXIS2_PLACEMENT_3D('',#795,#796,#797);
#799=CYLINDRICAL_SURFACE('',#798,0.5);
#800=ORIENTED_EDGE('',*,*,#375,.F.);
#801=DIRECTION('',(0.393994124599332,0.890519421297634,0.227472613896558));
#802=VECTOR('',#801,1.);
#803=CARTESIAN_POINT('',(1.44381794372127,5.86843262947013,1.21429947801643));
#804=LINE('',#803,#802);
#805=EDGE_CURVE('E505',#735,#365,#804,.F.);
#806=ORIENTED_EDGE('',*,*,#805,.F.);
#807=ORIENTED_EDGE('',*,*,#736,.F.);
#808=DIRECTION('',(0.393994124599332,0.890519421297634,0.227472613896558));
#809=VECTOR('',#808,1.);
#810=CARTESIAN_POINT('',(2.17076157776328,6.7662848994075,0.872578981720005));
#811=LINE('',#810,#809);
#812=EDGE_CURVE('E485',#374,#726,#811,.T.);
#813=ORIENTED_EDGE('',*,*,#812,.F.);
#814=EDGE_LOOP('',(#800,#806,#807,#813));
#815=FACE_BOUND('',#814,.T.);
#816=ADVANCED_FACE('F606',(#815),#799,.T.);
#817=CARTESIAN_POINT('',(1.3856406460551,6.,0.800000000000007));
#818=DIRECTION('',(-0.909489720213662,0.342020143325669,0.236327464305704));
#819=DIRECTION('',(-0.351990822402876,-0.93600345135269,0.));
#820=AXIS2_PLACEMENT_3D('',#817,#818,#819);
#821=PLANE('',#820);
#822=ORIENTED_EDGE('',*,*,#805,.T.);
#823=ORIENTED_EDGE('',*,*,#366,.T.);
#824=ORIENTED_EDGE('',*,*,#790,.T.);
#825=ORIENTED_EDGE('',*,*,#744,.F.);
#826=EDGE_LOOP('',(#822,#823,#824,#825));
#827=FACE_BOUND('',#826,.T.);
#828=ADVANCED_FACE('F599',(#827),#821,.T.);
#829=CARTESIAN_POINT('',(4.18048421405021,5.72260212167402,0.475638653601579));
#830=DIRECTION('',(0.189535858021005,-0.900138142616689,-0.392208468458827));
#831=DIRECTION('',(0.,0.399448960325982,-0.916755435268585));
#832=AXIS2_PLACEMENT_3D('',#829,#830,#831);
#833=CYLINDRICAL_SURFACE('',#832,0.5);
#834=ORIENTED_EDGE('',*,*,#392,.F.);
#835=DIRECTION('',(-0.189535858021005,0.900138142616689,0.392208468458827));
#836=VECTOR('',#835,1.);
#837=CARTESIAN_POINT('',(4.05544457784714,5.89361219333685,0.0227361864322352));
#838=LINE('',#837,#836);
#839=EDGE_CURVE('E487',#718,#382,#838,.F.);
#840=ORIENTED_EDGE('',*,*,#839,.F.);
#841=ORIENTED_EDGE('',*,*,#719,.F.);
#842=DIRECTION('',(-0.189535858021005,0.900138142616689,0.392208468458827));
#843=VECTOR('',#842,1.);
#844=CARTESIAN_POINT('',(4.40969877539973,6.85931266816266,0.712970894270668));
#845=LINE('',#844,#843);
#846=EDGE_CURVE('E493',#391,#709,#845,.T.);
#847=ORIENTED_EDGE('',*,*,#846,.F.);
#848=EDGE_LOOP('',(#834,#840,#841,#847));
#849=FACE_BOUND('',#848,.T.);
#850=ADVANCED_FACE('F595',(#849),#833,.T.);
#851=CARTESIAN_POINT('',(4.4298970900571,6.,-0.0404739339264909));
#852=DIRECTION('',(-0.250079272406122,0.342020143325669,-0.905804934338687));
#853=DIRECTION('',(0.,0.935531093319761,0.353244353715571));
#854=AXIS2_PLACEMENT_3D('',#851,#852,#853);
#855=PLANE('',#854);
#856=ORIENTED_EDGE('',*,*,#839,.T.);
#857=ORIENTED_EDGE('',*,*,#383,.T.);
#858=ORIENTED_EDGE('',*,*,#812,.T.);
#859=ORIENTED_EDGE('',*,*,#727,.F.);
#860=EDGE_LOOP('',(#856,#857,#858,#859));
#861=FACE_BOUND('',#860,.T.);
#862=ADVANCED_FACE('F598',(#861),#855,.T.);
#863=CARTESIAN_POINT('',(5.32845686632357,5.60873322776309,3.07638600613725));
#864=DIRECTION('',(0.448030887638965,-0.855779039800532,0.258670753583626));
#865=DIRECTION('',(0.88593122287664,0.463816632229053,0.));
#866=AXIS2_PLACEMENT_3D('',#863,#864,#865);
#867=CYLINDRICAL_SURFACE('',#866,0.5);
#868=ORIENTED_EDGE('',*,*,#407,.F.);
#869=DIRECTION('',(-0.448030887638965,0.855779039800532,-0.258670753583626));
#870=VECTOR('',#869,1.);
#871=CARTESIAN_POINT('',(5.76101229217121,5.77974329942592,2.8929429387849));
#872=LINE('',#871,#870);
#873=EDGE_CURVE('E490',#707,#399,#872,.F.);
#874=ORIENTED_EDGE('',*,*,#873,.F.);
#875=ORIENTED_EDGE('',*,*,#768,.F.);
#876=DIRECTION('',(-0.448030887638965,0.855779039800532,-0.258670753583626));
#877=VECTOR('',#876,1.);
#878=CARTESIAN_POINT('',(4.6942604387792,7.10077598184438,3.14341158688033));
#879=LINE('',#878,#877);
#880=EDGE_CURVE('E508',#348,#760,#879,.T.);
#881=ORIENTED_EDGE('',*,*,#880,.F.);
#882=EDGE_LOOP('',(#868,#874,#875,#881));
#883=FACE_BOUND('',#882,.T.);
#884=ADVANCED_FACE('F601',(#883),#867,.T.);
#885=CARTESIAN_POINT('',(5.88897274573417,6.,3.40000000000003));
#886=DIRECTION('',(0.865110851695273,0.342020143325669,-0.366886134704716));
#887=DIRECTION('',(-0.390432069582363,0.,-0.920631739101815));
#888=AXIS2_PLACEMENT_3D('',#885,#886,#887);
#889=PLANE('',#888);
#890=ORIENTED_EDGE('',*,*,#873,.T.);
#891=ORIENTED_EDGE('',*,*,#400,.T.);
#892=ORIENTED_EDGE('',*,*,#846,.T.);
#893=ORIENTED_EDGE('',*,*,#710,.F.);
#894=EDGE_LOOP('',(#890,#891,#892,#893));
#895=FACE_BOUND('',#894,.T.);
#896=ADVANCED_FACE('F604',(#895),#889,.T.);
#897=CARTESIAN_POINT('',(2.17989709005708,6.,3.85664038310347));
#898=DIRECTION('',(0.114822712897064,0.342020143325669,0.932651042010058));
#899=DIRECTION('',(0.,-0.938860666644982,0.344297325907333));
#900=AXIS2_PLACEMENT_3D('',#897,#898,#899);
#901=PLANE('',#900);
#902=ORIENTED_EDGE('',*,*,#783,.T.);
#903=ORIENTED_EDGE('',*,*,#349,.T.);
#904=ORIENTED_EDGE('',*,*,#880,.T.);
#905=ORIENTED_EDGE('',*,*,#761,.F.);
#906=EDGE_LOOP('',(#902,#903,#904,#905));
#907=FACE_BOUND('',#906,.T.);
#908=ADVANCED_FACE('F661',(#907),#901,.T.);
#909=CARTESIAN_POINT('',(0.,7.,0.));
#910=DIRECTION('',(0.,-1.,0.));
#911=DIRECTION('',(-0.866025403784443,0.,0.499999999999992));
#912=AXIS2_PLACEMENT_3D('',#909,#910,#911);
#913=PLANE('',#912);
#914=DIRECTION('',(-0.9925065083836,0.,-0.122191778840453));
#915=VECTOR('',#914,1.);
#916=CARTESIAN_POINT('',(-0.455791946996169,7.,3.70218420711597));
#917=LINE('',#916,#915);
#918=CARTESIAN_POINT('',(-4.74702026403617,7.,3.17387248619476));
#919=VERTEX_POINT('',#918);
#920=CARTESIAN_POINT('',(-2.86057615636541,7.,3.40612079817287));
#921=VERTEX_POINT('',#920);
#922=EDGE_CURVE('E421',#919,#921,#917,.F.);
#923=ORIENTED_EDGE('',*,*,#922,.T.);
#924=CARTESIAN_POINT('',(-2.84969036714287,7.,2.87135480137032));
#925=DIRECTION('',(0.,-1.,0.));
#926=DIRECTION('',(0.562194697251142,0.,0.827004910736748));
#927=AXIS2_PLACEMENT_3D('',#924,#925,#926);
#928=ELLIPSE('',#927,0.555470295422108,0.5);
#929=CARTESIAN_POINT('',(-2.34841993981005,7.,3.0579590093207));
#930=VERTEX_POINT('',#929);
#931=EDGE_CURVE('E475',#921,#930,#928,.F.);
#932=ORIENTED_EDGE('',*,*,#931,.T.);
#933=DIRECTION('',(-0.251494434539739,0.,0.967858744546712));
#934=VECTOR('',#933,1.);
#935=CARTESIAN_POINT('',(-1.45554254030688,7.,-0.378217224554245));
#936=LINE('',#935,#934);
#937=CARTESIAN_POINT('',(-1.94445935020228,7.,1.50334492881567));
#938=VERTEX_POINT('',#937);
#939=EDGE_CURVE('E424',#930,#938,#936,.F.);
#940=ORIENTED_EDGE('',*,*,#939,.T.);
#941=CARTESIAN_POINT('',(-2.47486450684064,7.,1.42886368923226));
#942=DIRECTION('',(0.,-1.,0.));
#943=DIRECTION('',(0.866025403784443,0.,-0.499999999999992));
#944=AXIS2_PLACEMENT_3D('',#941,#942,#943);
#945=ELLIPSE('',#944,0.561470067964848,0.5);
#946=CARTESIAN_POINT('',(-2.27416457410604,7.,0.932278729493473));
#947=VERTEX_POINT('',#946);
#948=EDGE_CURVE('E473',#938,#947,#945,.F.);
#949=ORIENTED_EDGE('',*,*,#948,.T.);
#950=DIRECTION('',(0.96393747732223,0.,0.266128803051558));
#951=VECTOR('',#950,1.);
#952=CARTESIAN_POINT('',(-0.400225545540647,7.,1.44964542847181));
#953=LINE('',#952,#951);
#954=CARTESIAN_POINT('',(-3.82248015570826,7.,0.504811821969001));
#955=VERTEX_POINT('',#954);
#956=EDGE_CURVE('E427',#947,#955,#953,.F.);
#957=ORIENTED_EDGE('',*,*,#956,.T.);
#958=CARTESIAN_POINT('',(-3.91151138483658,7.,1.03222685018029));
#959=DIRECTION('',(0.,-1.,0.));
#960=DIRECTION('',(-0.435109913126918,0.,-0.900377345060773));
#961=AXIS2_PLACEMENT_3D('',#958,#959,#960);
#962=ELLIPSE('',#961,0.555470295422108,0.5);
#963=CARTESIAN_POINT('',(-4.38007521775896,7.,0.774271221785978));
#964=VERTEX_POINT('',#963);
#965=EDGE_CURVE('E471',#955,#964,#962,.F.);
#966=ORIENTED_EDGE('',*,*,#965,.T.);
#967=DIRECTION('',(0.390432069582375,0.,-0.92063173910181));
#968=VECTOR('',#967,1.);
#969=CARTESIAN_POINT('',(-3.43408154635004,7.,-1.45636469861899));
#970=LINE('',#969,#968);
#971=CARTESIAN_POINT('',(-5.12216433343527,7.,2.52410389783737));
#972=VERTEX_POINT('',#971);
#973=EDGE_CURVE('E418',#964,#972,#970,.F.);
#974=ORIENTED_EDGE('',*,*,#973,.T.);
#975=CARTESIAN_POINT('',(-4.60007902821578,7.,2.65585686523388));
#976=DIRECTION('',(0.,-1.,0.));
#977=DIRECTION('',(-0.866025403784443,0.,0.499999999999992));
#978=AXIS2_PLACEMENT_3D('',#975,#976,#977);
#979=ELLIPSE('',#978,0.584262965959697,0.5);
#980=EDGE_CURVE('E469',#972,#919,#979,.F.);
#981=ORIENTED_EDGE('',*,*,#980,.T.);
#982=EDGE_LOOP('',(#923,#932,#940,#949,#957,#966,#974,#981));
#983=FACE_BOUND('',#982,.T.);
#984=ADVANCED_FACE('F594',(#983),#913,.F.);
#985=CARTESIAN_POINT('',(-4.18048421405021,5.72260212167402,0.47563865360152));
#986=DIRECTION('',(-0.189535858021,-0.900138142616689,-0.39220846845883));
#987=DIRECTION('',(0.,0.399448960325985,-0.916755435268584));
#988=AXIS2_PLACEMENT_3D('',#985,#986,#987);
#989=CYLINDRICAL_SURFACE('',#988,0.5);
#990=ORIENTED_EDGE('',*,*,#288,.F.);
#991=DIRECTION('',(0.189535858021,0.900138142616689,0.39220846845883));
#992=VECTOR('',#991,1.);
#993=CARTESIAN_POINT('',(-4.61303963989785,5.89361219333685,0.292195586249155));
#994=LINE('',#993,#992);
#995=EDGE_CURVE('E483',#964,#276,#994,.F.);
#996=ORIENTED_EDGE('',*,*,#995,.F.);
#997=ORIENTED_EDGE('',*,*,#965,.F.);
#998=DIRECTION('',(0.189535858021,0.900138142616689,0.39220846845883));
#999=VECTOR('',#998,1.);
#1000=CARTESIAN_POINT('',(-3.88360440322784,6.70971051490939,0.378326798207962));
#1001=LINE('',#1000,#999);
#1002=EDGE_CURVE('E477',#287,#955,#1001,.T.);
#1003=ORIENTED_EDGE('',*,*,#1002,.F.);
#1004=EDGE_LOOP('',(#990,#996,#997,#1003));
#1005=FACE_BOUND('',#1004,.T.);
#1006=ADVANCED_FACE('F590',(#1005),#989,.T.);
#1007=CARTESIAN_POINT('',(-1.89856280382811,5.6974225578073,1.09613574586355));
#1008=DIRECTION('',(0.393994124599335,-0.890519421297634,-0.227472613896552));
#1009=DIRECTION('',(0.914493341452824,0.404600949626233,0.));
#1010=AXIS2_PLACEMENT_3D('',#1007,#1008,#1009);
#1011=CYLINDRICAL_SURFACE('',#1010,0.5);
#1012=ORIENTED_EDGE('',*,*,#305,.F.);
#1013=DIRECTION('',(-0.393994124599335,0.890519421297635,0.227472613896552));
#1014=VECTOR('',#1013,1.);
#1015=CARTESIAN_POINT('',(-1.77352316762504,5.86843262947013,0.643233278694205));
#1016=LINE('',#1015,#1014);
#1017=EDGE_CURVE('E479',#947,#295,#1016,.F.);
#1018=ORIENTED_EDGE('',*,*,#1017,.F.);
#1019=ORIENTED_EDGE('',*,*,#948,.F.);
#1020=DIRECTION('',(-0.393994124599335,0.890519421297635,0.227472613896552));
#1021=VECTOR('',#1020,1.);
#1022=CARTESIAN_POINT('',(-1.84105635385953,6.7662848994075,1.44364518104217));
#1023=LINE('',#1022,#1021);
#1024=EDGE_CURVE('E459',#304,#938,#1023,.T.);
#1025=ORIENTED_EDGE('',*,*,#1024,.F.);
#1026=EDGE_LOOP('',(#1012,#1018,#1019,#1025));
#1027=FACE_BOUND('',#1026,.T.);
#1028=ADVANCED_FACE('F587',(#1027),#1011,.T.);
#1029=CARTESIAN_POINT('',(-1.38564064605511,6.,0.799999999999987));
#1030=DIRECTION('',(0.250079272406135,0.342020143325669,-0.905804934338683));
#1031=DIRECTION('',(0.,0.935531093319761,0.353244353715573));
#1032=AXIS2_PLACEMENT_3D('',#1029,#1030,#1031);
#1033=PLANE('',#1032);
#1034=ORIENTED_EDGE('',*,*,#1017,.T.);
#1035=ORIENTED_EDGE('',*,*,#296,.T.);
#1036=ORIENTED_EDGE('',*,*,#1002,.T.);
#1037=ORIENTED_EDGE('',*,*,#956,.F.);
#1038=EDGE_LOOP('',(#1034,#1035,#1036,#1037));
#1039=FACE_BOUND('',#1038,.T.);
#1040=ADVANCED_FACE('F580',(#1039),#1033,.T.);
#1041=CARTESIAN_POINT('',(-2.50215726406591,5.72260212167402,3.3825862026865));
#1042=DIRECTION('',(0.244894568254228,-0.900138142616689,0.360247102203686));
#1043=DIRECTION('',(0.,-0.37156124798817,-0.928408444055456));
#1044=AXIS2_PLACEMENT_3D('',#1041,#1042,#1043);
#1045=CYLINDRICAL_SURFACE('',#1044,0.5);
#1046=ORIENTED_EDGE('',*,*,#322,.F.);
#1047=DIRECTION('',(-0.244894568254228,0.900138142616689,-0.360247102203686));
#1048=VECTOR('',#1047,1.);
#1049=CARTESIAN_POINT('',(-2.04741240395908,5.89361219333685,3.50074993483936));
#1050=LINE('',#1049,#1048);
#1051=EDGE_CURVE('E461',#930,#312,#1050,.F.);
#1052=ORIENTED_EDGE('',*,*,#1051,.F.);
#1053=ORIENTED_EDGE('',*,*,#931,.F.);
#1054=DIRECTION('',(-0.244894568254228,0.900138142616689,-0.360247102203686));
#1055=VECTOR('',#1054,1.);
#1056=CARTESIAN_POINT('',(-2.82230029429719,6.85931266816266,3.46242571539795));
#1057=LINE('',#1056,#1055);
#1058=EDGE_CURVE('E467',#321,#921,#1057,.T.);
#1059=ORIENTED_EDGE('',*,*,#1058,.F.);
#1060=EDGE_LOOP('',(#1046,#1052,#1053,#1059));
#1061=FACE_BOUND('',#1060,.T.);
#1062=ADVANCED_FACE('F576',(#1061),#1045,.T.);
#1063=CARTESIAN_POINT('',(-2.17989709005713,6.,3.85664038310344));
#1064=DIRECTION('',(0.909489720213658,0.342020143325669,0.236327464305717));
#1065=DIRECTION('',(-0.351990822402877,0.936003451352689,0.));
#1066=AXIS2_PLACEMENT_3D('',#1063,#1064,#1065);
#1067=PLANE('',#1066);
#1068=ORIENTED_EDGE('',*,*,#1051,.T.);
#1069=ORIENTED_EDGE('',*,*,#313,.T.);
#1070=ORIENTED_EDGE('',*,*,#1024,.T.);
#1071=ORIENTED_EDGE('',*,*,#939,.F.);
#1072=EDGE_LOOP('',(#1068,#1069,#1070,#1071));
#1073=FACE_BOUND('',#1072,.T.);
#1074=ADVANCED_FACE('F579',(#1073),#1067,.T.);
#1075=CARTESIAN_POINT('',(-5.32845686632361,5.60873322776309,3.07638600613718));
#1076=DIRECTION('',(-0.448030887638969,-0.855779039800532,0.25867075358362));
#1077=DIRECTION('',(0.885931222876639,-0.463816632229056,0.));
#1078=AXIS2_PLACEMENT_3D('',#1075,#1076,#1077);
#1079=CYLINDRICAL_SURFACE('',#1078,0.5);
#1080=ORIENTED_EDGE('',*,*,#337,.F.);
#1081=DIRECTION('',(0.448030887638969,0.855779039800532,-0.25867075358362));
#1082=VECTOR('',#1081,1.);
#1083=CARTESIAN_POINT('',(-5.38586822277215,5.77974329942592,3.54271152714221));
#1084=LINE('',#1083,#1082);
#1085=EDGE_CURVE('E464',#919,#329,#1084,.F.);
#1086=ORIENTED_EDGE('',*,*,#1085,.F.);
#1087=ORIENTED_EDGE('',*,*,#980,.F.);
#1088=DIRECTION('',(0.448030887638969,0.855779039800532,-0.25867075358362));
#1089=VECTOR('',#1088,1.);
#1090=CARTESIAN_POINT('',(-5.06940450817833,7.10077598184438,2.49364299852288));
#1091=LINE('',#1090,#1089);
#1092=EDGE_CURVE('E481',#278,#972,#1091,.T.);
#1093=ORIENTED_EDGE('',*,*,#1092,.F.);
#1094=EDGE_LOOP('',(#1080,#1086,#1087,#1093));
#1095=FACE_BOUND('',#1094,.T.);
#1096=ADVANCED_FACE('F582',(#1095),#1079,.T.);
#1097=CARTESIAN_POINT('',(-5.88897274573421,6.,3.39999999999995));
#1098=DIRECTION('',(-0.114822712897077,0.342020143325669,0.932651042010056));
#1099=DIRECTION('',(0.,-0.938860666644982,0.344297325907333));
#1100=AXIS2_PLACEMENT_3D('',#1097,#1098,#1099);
#1101=PLANE('',#1100);
#1102=ORIENTED_EDGE('',*,*,#1085,.T.);
#1103=ORIENTED_EDGE('',*,*,#330,.T.);
#1104=ORIENTED_EDGE('',*,*,#1058,.T.);
#1105=ORIENTED_EDGE('',*,*,#922,.F.);
#1106=EDGE_LOOP('',(#1102,#1103,#1104,#1105));
#1107=FACE_BOUND('',#1106,.T.);
#1108=ADVANCED_FACE('F585',(#1107),#1101,.T.);
#1109=CARTESIAN_POINT('',(-4.42989709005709,6.,-0.0404739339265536));
#1110=DIRECTION('',(-0.865110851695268,0.342020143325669,-0.366886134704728));
#1111=DIRECTION('',(-0.390432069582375,0.,0.92063173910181));
#1112=AXIS2_PLACEMENT_3D('',#1109,#1110,#1111);
#1113=PLANE('',#1112);
#1114=ORIENTED_EDGE('',*,*,#995,.T.);
#1115=ORIENTED_EDGE('',*,*,#279,.T.);
#1116=ORIENTED_EDGE('',*,*,#1092,.T.);
#1117=ORIENTED_EDGE('',*,*,#973,.F.);
#1118=EDGE_LOOP('',(#1114,#1115,#1116,#1117));
#1119=FACE_BOUND('',#1118,.T.);
#1120=ADVANCED_FACE('F663',(#1119),#1113,.T.);
#1121=CLOSED_SHELL('',(#185,#205,#225,#245,#265,#484,#560,#582,#604,#616,#638,#650,#672,#684,
#696,#772,#794,#816,#828,#850,#862,#884,#896,#908,#984,#1006,#1028,#1040,#1062,#1074,#1096,
#1108,#1120));
#1122=MANIFOLD_SOLID_BREP('B6',#1121);
#1123=ADVANCED_BREP_SHAPE_REPRESENTATION('',(#18,#168,#1122),#14);
#1124=SHAPE_DEFINITION_REPRESENTATION(#9,#1123);
ENDSEC;
END-ISO-10303-21;
